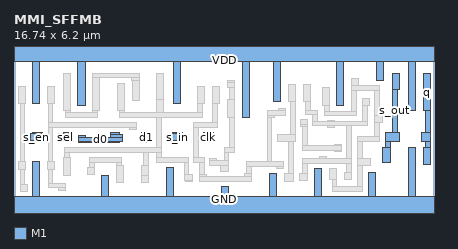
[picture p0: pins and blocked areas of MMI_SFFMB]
MACRO MMI_SFFMB
	CLASS CORE ;
	FOREIGN MMI_SFFMB 0 0 ;
	SIZE 16.74 BY 6.2 ;
	SYMMETRY X Y ;
	SITE CORE1 ;
	PIN d0
		DIRECTION input ;
		USE SIGNAL ;
		PORT
			LAYER M1 ;
			RECT 3.84 2.885 4.22 2.98 ;
			LAYER M1 ;
			RECT 2.565 2.755 2.845 2.84 ;
			LAYER M1 ;
			RECT 3.84 2.755 4.305 2.885 ;
			LAYER M1 ;
			RECT 2.565 2.605 4.305 2.755 ;
			LAYER M1 ;
			RECT 2.565 2.565 4.22 2.605 ;
			LAYER M1 ;
			RECT 2.565 2.56 2.845 2.565 ;
		END
		AntennaGateArea 0.3465 ;
	END d0
	PIN sel
		DIRECTION input ;
		USE SIGNAL ;
		PORT
			LAYER M1 ;
			RECT 1.98 2.93 2.36 2.98 ;
			LAYER M1 ;
			RECT 1.755 2.65 2.36 2.93 ;
			LAYER M1 ;
			RECT 1.98 2.6 2.36 2.65 ;
		END
		AntennaGateArea 0.51975 ;
	END sel
	PIN GND
		DIRECTION inout ;
		USE GROUND ;
		PORT
			LAYER M1 ;
			RECT 0.75 0.42 1.03 1.82 ;
			LAYER M1 ;
			RECT 3.505 0.42 3.785 1.25 ;
			LAYER M1 ;
			RECT 6.07 0.42 6.35 1.575 ;
			LAYER M1 ;
			RECT 8.265 0.42 8.545 0.835 ;
			LAYER M1 ;
			RECT 10.175 0.42 10.455 1.335 ;
			LAYER M1 ;
			RECT 11.995 0.42 12.275 1.54 ;
			LAYER M1 ;
			RECT 14.135 0.42 14.415 1.375 ;
			LAYER M1 ;
			RECT 15.715 0.42 15.995 2.39 ;
			LAYER M1 ;
			RECT 0 -0.42 16.745 0.42 ;
		END
	END GND
	PIN q
		DIRECTION output ;
		USE SIGNAL ;
		PORT
			LAYER M1 ;
			RECT 16.305 3.845 16.585 5.315 ;
			LAYER M1 ;
			RECT 16.395 2.98 16.585 3.845 ;
			LAYER M1 ;
			RECT 16.24 2.6 16.62 2.98 ;
			LAYER M1 ;
			RECT 16.395 2.39 16.585 2.6 ;
			LAYER M1 ;
			RECT 16.305 1.69 16.585 2.39 ;
		END
		AntennaDiffArea 0.91245 ;
	END q
	PIN s_in
		DIRECTION input ;
		USE SIGNAL ;
		PORT
			LAYER M1 ;
			RECT 6.32 2.915 6.7 2.98 ;
			LAYER M1 ;
			RECT 6.32 2.635 6.735 2.915 ;
			LAYER M1 ;
			RECT 6.32 2.6 6.7 2.635 ;
		END
		AntennaGateArea 0.17325 ;
	END s_in
	PIN s_en
		DIRECTION input ;
		USE SIGNAL ;
		PORT
			LAYER M1 ;
			RECT 0.74 2.93 1.12 2.98 ;
			LAYER M1 ;
			RECT 0.64 2.65 1.12 2.93 ;
			LAYER M1 ;
			RECT 0.74 2.6 1.12 2.65 ;
		END
		AntennaGateArea 0.9045 ;
	END s_en
	PIN d1
		DIRECTION input ;
		USE SIGNAL ;
		PORT
			LAYER M1 ;
			RECT 5.08 2.6 5.46 2.98 ;
			LAYER M1 ;
			RECT 5.175 2.565 5.455 2.6 ;
		END
		AntennaGateArea 0.3465 ;
	END d1
	PIN VDD
		DIRECTION inout ;
		USE POWER ;
		PORT
			LAYER M1 ;
			RECT 0 5.78 16.745 6.62 ;
			LAYER M1 ;
			RECT 0.75 4.115 1.03 5.78 ;
			LAYER M1 ;
			RECT 2.55 4.065 2.83 5.78 ;
			LAYER M1 ;
			RECT 6.345 4.115 6.625 5.78 ;
			LAYER M1 ;
			RECT 9.09 3.565 9.37 5.78 ;
			LAYER M1 ;
			RECT 10.345 4.19 10.625 5.78 ;
			LAYER M1 ;
			RECT 12.87 4.065 13.15 5.78 ;
			LAYER M1 ;
			RECT 14.465 5.03 14.745 5.78 ;
			LAYER M1 ;
			RECT 15.715 3.845 15.995 5.78 ;
		END
	END VDD
	PIN s_out
		DIRECTION output ;
		USE SIGNAL ;
		PORT
			LAYER M1 ;
			RECT 15.075 4.68 15.355 5.315 ;
			LAYER M1 ;
			RECT 15.075 2.98 15.27 4.68 ;
			LAYER M1 ;
			RECT 14.8 2.6 15.38 2.98 ;
			LAYER M1 ;
			RECT 14.8 2.39 14.99 2.6 ;
			LAYER M1 ;
			RECT 14.705 1.755 14.99 2.39 ;
		END
		AntennaDiffArea 0.588675 ;
	END s_out
	PIN clk
		DIRECTION input ;
		USE CLOCK ;
		PORT
			LAYER M1 ;
			RECT 7.56 2.6 7.94 2.98 ;
		END
		AntennaGateArea 0.44625 ;
	END clk
	OBS
		LAYER M1 ;
		RECT 0.16 4.115 0.44 4.815 ;
		LAYER M1 ;
		RECT 1.34 4.115 1.62 4.815 ;
		LAYER M1 ;
		RECT 0.245 1.82 0.435 4.115 ;
		LAYER M1 ;
		RECT 1.36 3.37 1.55 4.115 ;
		LAYER M1 ;
		RECT 1.955 3.845 2.235 5.315 ;
		LAYER M1 ;
		RECT 3.145 5.31 4.895 5.34 ;
		LAYER M1 ;
		RECT 3.145 5.145 4.99 5.31 ;
		LAYER M1 ;
		RECT 2.04 3.76 2.235 3.845 ;
		LAYER M1 ;
		RECT 3.145 3.845 3.425 5.145 ;
		LAYER M1 ;
		RECT 4.7 5.055 4.99 5.145 ;
		LAYER M1 ;
		RECT 4.12 3.845 4.4 4.905 ;
		LAYER M1 ;
		RECT 4.71 4.25 4.99 5.055 ;
		LAYER M1 ;
		RECT 5.67 4.265 5.95 5.315 ;
		LAYER M1 ;
		RECT 3.145 3.76 3.34 3.845 ;
		LAYER M1 ;
		RECT 2.04 3.57 3.34 3.76 ;
		LAYER M1 ;
		RECT 4.205 3.765 4.4 3.845 ;
		LAYER M1 ;
		RECT 5.665 3.765 5.95 4.265 ;
		LAYER M1 ;
		RECT 8.49 4.96 8.77 5.06 ;
		LAYER M1 ;
		RECT 7.31 4.115 7.59 4.815 ;
		LAYER M1 ;
		RECT 7.9 4.115 8.18 4.815 ;
		LAYER M1 ;
		RECT 8.49 4.78 8.775 4.96 ;
		LAYER M1 ;
		RECT 8.58 4.265 8.775 4.78 ;
		LAYER M1 ;
		RECT 7.315 3.765 7.505 4.115 ;
		LAYER M1 ;
		RECT 4.205 3.57 7.505 3.765 ;
		LAYER M1 ;
		RECT 1.36 3.18 4.88 3.37 ;
		LAYER M1 ;
		RECT 1.36 1.82 1.55 3.18 ;
		LAYER M1 ;
		RECT 4.6 3.09 4.88 3.18 ;
		LAYER M1 ;
		RECT 5.665 2.36 5.86 3.57 ;
		LAYER M1 ;
		RECT 7.9 3.37 8.095 4.115 ;
		LAYER M1 ;
		RECT 8.5 3.565 8.78 4.265 ;
		LAYER M1 ;
		RECT 10.935 4.19 11.215 4.89 ;
		LAYER M1 ;
		RECT 11.525 4.19 11.815 4.89 ;
		LAYER M1 ;
		RECT 10.54 3.845 10.82 3.935 ;
		LAYER M1 ;
		RECT 10.09 3.655 10.82 3.845 ;
		LAYER M1 ;
		RECT 10.09 3.565 10.375 3.655 ;
		LAYER M1 ;
		RECT 7.17 3.18 8.095 3.37 ;
		LAYER M1 ;
		RECT 2.03 2.17 5.86 2.36 ;
		LAYER M1 ;
		RECT 2.03 1.955 2.225 2.17 ;
		LAYER M1 ;
		RECT 0.16 1.505 0.44 1.82 ;
		LAYER M1 ;
		RECT 0.245 0.905 0.435 1.505 ;
		LAYER M1 ;
		RECT 0.245 0.625 0.545 0.905 ;
		LAYER M1 ;
		RECT 1.34 1.505 1.62 1.82 ;
		LAYER M1 ;
		RECT 1.36 0.955 1.55 1.505 ;
		LAYER M1 ;
		RECT 1.955 1.255 2.235 1.955 ;
		LAYER M1 ;
		RECT 3 1.78 4.285 1.97 ;
		LAYER M1 ;
		RECT 3 1.575 3.195 1.78 ;
		LAYER M1 ;
		RECT 2.915 1.295 3.195 1.575 ;
		LAYER M1 ;
		RECT 3 1.29 3.195 1.295 ;
		LAYER M1 ;
		RECT 4.095 1.67 4.285 1.78 ;
		LAYER M1 ;
		RECT 5.17 1.67 5.365 2.17 ;
		LAYER M1 ;
		RECT 5.665 1.97 5.86 2.17 ;
		LAYER M1 ;
		RECT 7.17 1.975 7.36 3.18 ;
		LAYER M1 ;
		RECT 8.58 2.365 8.775 3.565 ;
		LAYER M1 ;
		RECT 8.37 2.17 8.775 2.365 ;
		LAYER M1 ;
		RECT 5.665 1.78 6.97 1.97 ;
		LAYER M1 ;
		RECT 7.17 1.78 7.6 1.975 ;
		LAYER M1 ;
		RECT 1.36 0.765 2.055 0.955 ;
		LAYER M1 ;
		RECT 1.775 0.675 2.055 0.765 ;
		LAYER M1 ;
		RECT 4.095 0.97 4.375 1.67 ;
		LAYER M1 ;
		RECT 5.065 1.265 5.365 1.67 ;
		LAYER M1 ;
		RECT 5.065 0.97 5.345 1.265 ;
		LAYER M1 ;
		RECT 6.78 1.31 6.97 1.78 ;
		LAYER M1 ;
		RECT 7.41 1.31 7.6 1.78 ;
		LAYER M1 ;
		RECT 7.81 1.84 8.09 1.925 ;
		LAYER M1 ;
		RECT 8.37 1.84 8.565 2.17 ;
		LAYER M1 ;
		RECT 7.81 1.645 8.565 1.84 ;
		LAYER M1 ;
		RECT 10.09 1.815 10.28 3.565 ;
		LAYER M1 ;
		RECT 11.02 2.905 11.21 4.19 ;
		LAYER M1 ;
		RECT 11.625 3.865 11.815 4.19 ;
		LAYER M1 ;
		RECT 12.28 4.065 12.56 4.765 ;
		LAYER M1 ;
		RECT 13.445 4.83 13.725 5.125 ;
		LAYER M1 ;
		RECT 13.44 4.64 14.55 4.83 ;
		LAYER M1 ;
		RECT 11.625 3.67 12.095 3.865 ;
		LAYER M1 ;
		RECT 11.415 3.3 11.695 3.47 ;
		LAYER M1 ;
		RECT 11.905 3.425 12.095 3.67 ;
		LAYER M1 ;
		RECT 12.37 3.82 12.56 4.065 ;
		LAYER M1 ;
		RECT 13.44 3.82 13.635 4.64 ;
		LAYER M1 ;
		RECT 12.37 3.63 13.635 3.82 ;
		LAYER M1 ;
		RECT 13.875 4.055 14.155 4.335 ;
		LAYER M1 ;
		RECT 12.48 3.425 12.76 3.43 ;
		LAYER M1 ;
		RECT 13.875 3.425 14.07 4.055 ;
		LAYER M1 ;
		RECT 11.415 3.19 11.7 3.3 ;
		LAYER M1 ;
		RECT 11.905 3.23 14.07 3.425 ;
		LAYER M1 ;
		RECT 14.355 3.635 14.55 4.64 ;
		LAYER M1 ;
		RECT 14.355 3.355 14.67 3.635 ;
		LAYER M1 ;
		RECT 10.78 2.9 11.21 2.905 ;
		LAYER M1 ;
		RECT 10.5 2.625 11.21 2.9 ;
		LAYER M1 ;
		RECT 10.5 2.62 11.145 2.625 ;
		LAYER M1 ;
		RECT 8.25 1.425 8.565 1.645 ;
		LAYER M1 ;
		RECT 9.255 1.625 10.755 1.815 ;
		LAYER M1 ;
		RECT 9.255 1.33 9.45 1.625 ;
		LAYER M1 ;
		RECT 10.475 1.535 10.755 1.625 ;
		LAYER M1 ;
		RECT 10.955 1.335 11.145 2.62 ;
		LAYER M1 ;
		RECT 11.505 2.45 11.7 3.19 ;
		LAYER M1 ;
		RECT 12.48 3.15 12.76 3.23 ;
		LAYER M1 ;
		RECT 12.775 2.45 13.055 2.49 ;
		LAYER M1 ;
		RECT 11.505 2.255 13.055 2.45 ;
		LAYER M1 ;
		RECT 12.775 2.21 13.055 2.255 ;
		LAYER M1 ;
		RECT 12.19 1.935 12.47 2.02 ;
		LAYER M1 ;
		RECT 13.26 1.935 13.45 3.23 ;
		LAYER M1 ;
		RECT 14.355 2.815 14.55 3.355 ;
		LAYER M1 ;
		RECT 6.78 1.04 7.1 1.31 ;
		LAYER M1 ;
		RECT 6.82 1.03 7.1 1.04 ;
		LAYER M1 ;
		RECT 7.41 1.225 7.69 1.31 ;
		LAYER M1 ;
		RECT 9.17 1.225 9.45 1.33 ;
		LAYER M1 ;
		RECT 7.41 1.035 9.45 1.225 ;
		LAYER M1 ;
		RECT 7.41 1.03 7.69 1.035 ;
		LAYER M1 ;
		RECT 10.765 1.02 11.145 1.335 ;
		LAYER M1 ;
		RECT 11.495 1.745 13.45 1.935 ;
		LAYER M1 ;
		RECT 11.495 1.33 11.685 1.745 ;
		LAYER M1 ;
		RECT 12.19 1.74 12.47 1.745 ;
		LAYER M1 ;
		RECT 11.395 1.075 11.685 1.33 ;
		LAYER M1 ;
		RECT 11.395 1.05 11.675 1.075 ;
		LAYER M1 ;
		RECT 10.955 1.015 11.145 1.02 ;
		LAYER M1 ;
		RECT 12.585 1.09 12.865 1.54 ;
		LAYER M1 ;
		RECT 13.26 1.375 13.45 1.745 ;
		LAYER M1 ;
		RECT 13.705 2.625 14.55 2.815 ;
		LAYER M1 ;
		RECT 13.705 1.92 13.9 2.625 ;
		LAYER M1 ;
		RECT 13.705 1.635 14.225 1.92 ;
		LAYER M1 ;
		RECT 13.175 1.095 13.455 1.375 ;
		LAYER M1 ;
		RECT 12.675 0.81 12.865 1.09 ;
		LAYER M1 ;
		RECT 13.705 0.81 13.9 1.635 ;
		LAYER M1 ;
		RECT 12.675 0.62 13.9 0.81 ;
	END
END MMI_SFFMB
